VERSION 5.7 ;
BUSBITCHARS "[]" ;
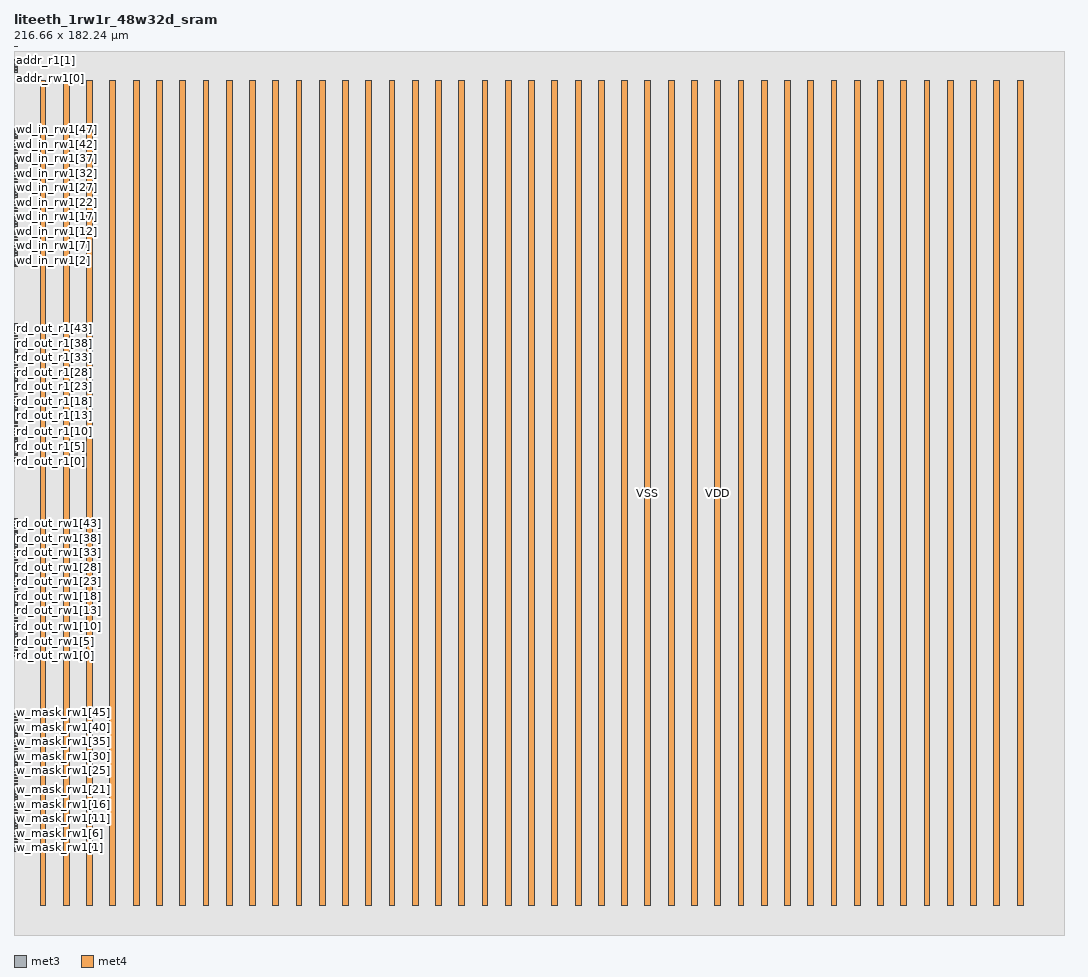
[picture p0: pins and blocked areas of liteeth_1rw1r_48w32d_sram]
MACRO liteeth_1rw1r_48w32d_sram
  FOREIGN liteeth_1rw1r_48w32d_sram 0 0 ;
  SYMMETRY X Y R90 ;
  SIZE 216.660 BY 182.240 ;
  CLASS BLOCK ;
  PIN w_mask_rw1[0]
    DIRECTION INPUT ;
    USE SIGNAL ;
    SHAPE ABUTMENT ;
    PORT
      LAYER met3 ;
      RECT 0.000 17.250 0.800 17.550 ;
    END
  END w_mask_rw1[0]
  PIN w_mask_rw1[1]
    DIRECTION INPUT ;
    USE SIGNAL ;
    SHAPE ABUTMENT ;
    PORT
      LAYER met3 ;
      RECT 0.000 17.850 0.800 18.150 ;
    END
  END w_mask_rw1[1]
  PIN w_mask_rw1[2]
    DIRECTION INPUT ;
    USE SIGNAL ;
    SHAPE ABUTMENT ;
    PORT
      LAYER met3 ;
      RECT 0.000 18.450 0.800 18.750 ;
    END
  END w_mask_rw1[2]
  PIN w_mask_rw1[3]
    DIRECTION INPUT ;
    USE SIGNAL ;
    SHAPE ABUTMENT ;
    PORT
      LAYER met3 ;
      RECT 0.000 19.050 0.800 19.350 ;
    END
  END w_mask_rw1[3]
  PIN w_mask_rw1[4]
    DIRECTION INPUT ;
    USE SIGNAL ;
    SHAPE ABUTMENT ;
    PORT
      LAYER met3 ;
      RECT 0.000 19.650 0.800 19.950 ;
    END
  END w_mask_rw1[4]
  PIN w_mask_rw1[5]
    DIRECTION INPUT ;
    USE SIGNAL ;
    SHAPE ABUTMENT ;
    PORT
      LAYER met3 ;
      RECT 0.000 20.250 0.800 20.550 ;
    END
  END w_mask_rw1[5]
  PIN w_mask_rw1[6]
    DIRECTION INPUT ;
    USE SIGNAL ;
    SHAPE ABUTMENT ;
    PORT
      LAYER met3 ;
      RECT 0.000 20.850 0.800 21.150 ;
    END
  END w_mask_rw1[6]
  PIN w_mask_rw1[7]
    DIRECTION INPUT ;
    USE SIGNAL ;
    SHAPE ABUTMENT ;
    PORT
      LAYER met3 ;
      RECT 0.000 21.450 0.800 21.750 ;
    END
  END w_mask_rw1[7]
  PIN w_mask_rw1[8]
    DIRECTION INPUT ;
    USE SIGNAL ;
    SHAPE ABUTMENT ;
    PORT
      LAYER met3 ;
      RECT 0.000 22.050 0.800 22.350 ;
    END
  END w_mask_rw1[8]
  PIN w_mask_rw1[9]
    DIRECTION INPUT ;
    USE SIGNAL ;
    SHAPE ABUTMENT ;
    PORT
      LAYER met3 ;
      RECT 0.000 22.650 0.800 22.950 ;
    END
  END w_mask_rw1[9]
  PIN w_mask_rw1[10]
    DIRECTION INPUT ;
    USE SIGNAL ;
    SHAPE ABUTMENT ;
    PORT
      LAYER met3 ;
      RECT 0.000 23.250 0.800 23.550 ;
    END
  END w_mask_rw1[10]
  PIN w_mask_rw1[11]
    DIRECTION INPUT ;
    USE SIGNAL ;
    SHAPE ABUTMENT ;
    PORT
      LAYER met3 ;
      RECT 0.000 23.850 0.800 24.150 ;
    END
  END w_mask_rw1[11]
  PIN w_mask_rw1[12]
    DIRECTION INPUT ;
    USE SIGNAL ;
    SHAPE ABUTMENT ;
    PORT
      LAYER met3 ;
      RECT 0.000 24.450 0.800 24.750 ;
    END
  END w_mask_rw1[12]
  PIN w_mask_rw1[13]
    DIRECTION INPUT ;
    USE SIGNAL ;
    SHAPE ABUTMENT ;
    PORT
      LAYER met3 ;
      RECT 0.000 25.050 0.800 25.350 ;
    END
  END w_mask_rw1[13]
  PIN w_mask_rw1[14]
    DIRECTION INPUT ;
    USE SIGNAL ;
    SHAPE ABUTMENT ;
    PORT
      LAYER met3 ;
      RECT 0.000 25.650 0.800 25.950 ;
    END
  END w_mask_rw1[14]
  PIN w_mask_rw1[15]
    DIRECTION INPUT ;
    USE SIGNAL ;
    SHAPE ABUTMENT ;
    PORT
      LAYER met3 ;
      RECT 0.000 26.250 0.800 26.550 ;
    END
  END w_mask_rw1[15]
  PIN w_mask_rw1[16]
    DIRECTION INPUT ;
    USE SIGNAL ;
    SHAPE ABUTMENT ;
    PORT
      LAYER met3 ;
      RECT 0.000 26.850 0.800 27.150 ;
    END
  END w_mask_rw1[16]
  PIN w_mask_rw1[17]
    DIRECTION INPUT ;
    USE SIGNAL ;
    SHAPE ABUTMENT ;
    PORT
      LAYER met3 ;
      RECT 0.000 27.450 0.800 27.750 ;
    END
  END w_mask_rw1[17]
  PIN w_mask_rw1[18]
    DIRECTION INPUT ;
    USE SIGNAL ;
    SHAPE ABUTMENT ;
    PORT
      LAYER met3 ;
      RECT 0.000 28.050 0.800 28.350 ;
    END
  END w_mask_rw1[18]
  PIN w_mask_rw1[19]
    DIRECTION INPUT ;
    USE SIGNAL ;
    SHAPE ABUTMENT ;
    PORT
      LAYER met3 ;
      RECT 0.000 28.650 0.800 28.950 ;
    END
  END w_mask_rw1[19]
  PIN w_mask_rw1[20]
    DIRECTION INPUT ;
    USE SIGNAL ;
    SHAPE ABUTMENT ;
    PORT
      LAYER met3 ;
      RECT 0.000 29.250 0.800 29.550 ;
    END
  END w_mask_rw1[20]
  PIN w_mask_rw1[21]
    DIRECTION INPUT ;
    USE SIGNAL ;
    SHAPE ABUTMENT ;
    PORT
      LAYER met3 ;
      RECT 0.000 29.850 0.800 30.150 ;
    END
  END w_mask_rw1[21]
  PIN w_mask_rw1[22]
    DIRECTION INPUT ;
    USE SIGNAL ;
    SHAPE ABUTMENT ;
    PORT
      LAYER met3 ;
      RECT 0.000 30.450 0.800 30.750 ;
    END
  END w_mask_rw1[22]
  PIN w_mask_rw1[23]
    DIRECTION INPUT ;
    USE SIGNAL ;
    SHAPE ABUTMENT ;
    PORT
      LAYER met3 ;
      RECT 0.000 31.050 0.800 31.350 ;
    END
  END w_mask_rw1[23]
  PIN w_mask_rw1[24]
    DIRECTION INPUT ;
    USE SIGNAL ;
    SHAPE ABUTMENT ;
    PORT
      LAYER met3 ;
      RECT 0.000 31.650 0.800 31.950 ;
    END
  END w_mask_rw1[24]
  PIN w_mask_rw1[25]
    DIRECTION INPUT ;
    USE SIGNAL ;
    SHAPE ABUTMENT ;
    PORT
      LAYER met3 ;
      RECT 0.000 32.250 0.800 32.550 ;
    END
  END w_mask_rw1[25]
  PIN w_mask_rw1[26]
    DIRECTION INPUT ;
    USE SIGNAL ;
    SHAPE ABUTMENT ;
    PORT
      LAYER met3 ;
      RECT 0.000 32.850 0.800 33.150 ;
    END
  END w_mask_rw1[26]
  PIN w_mask_rw1[27]
    DIRECTION INPUT ;
    USE SIGNAL ;
    SHAPE ABUTMENT ;
    PORT
      LAYER met3 ;
      RECT 0.000 33.450 0.800 33.750 ;
    END
  END w_mask_rw1[27]
  PIN w_mask_rw1[28]
    DIRECTION INPUT ;
    USE SIGNAL ;
    SHAPE ABUTMENT ;
    PORT
      LAYER met3 ;
      RECT 0.000 34.050 0.800 34.350 ;
    END
  END w_mask_rw1[28]
  PIN w_mask_rw1[29]
    DIRECTION INPUT ;
    USE SIGNAL ;
    SHAPE ABUTMENT ;
    PORT
      LAYER met3 ;
      RECT 0.000 34.650 0.800 34.950 ;
    END
  END w_mask_rw1[29]
  PIN w_mask_rw1[30]
    DIRECTION INPUT ;
    USE SIGNAL ;
    SHAPE ABUTMENT ;
    PORT
      LAYER met3 ;
      RECT 0.000 35.250 0.800 35.550 ;
    END
  END w_mask_rw1[30]
  PIN w_mask_rw1[31]
    DIRECTION INPUT ;
    USE SIGNAL ;
    SHAPE ABUTMENT ;
    PORT
      LAYER met3 ;
      RECT 0.000 35.850 0.800 36.150 ;
    END
  END w_mask_rw1[31]
  PIN w_mask_rw1[32]
    DIRECTION INPUT ;
    USE SIGNAL ;
    SHAPE ABUTMENT ;
    PORT
      LAYER met3 ;
      RECT 0.000 36.450 0.800 36.750 ;
    END
  END w_mask_rw1[32]
  PIN w_mask_rw1[33]
    DIRECTION INPUT ;
    USE SIGNAL ;
    SHAPE ABUTMENT ;
    PORT
      LAYER met3 ;
      RECT 0.000 37.050 0.800 37.350 ;
    END
  END w_mask_rw1[33]
  PIN w_mask_rw1[34]
    DIRECTION INPUT ;
    USE SIGNAL ;
    SHAPE ABUTMENT ;
    PORT
      LAYER met3 ;
      RECT 0.000 37.650 0.800 37.950 ;
    END
  END w_mask_rw1[34]
  PIN w_mask_rw1[35]
    DIRECTION INPUT ;
    USE SIGNAL ;
    SHAPE ABUTMENT ;
    PORT
      LAYER met3 ;
      RECT 0.000 38.250 0.800 38.550 ;
    END
  END w_mask_rw1[35]
  PIN w_mask_rw1[36]
    DIRECTION INPUT ;
    USE SIGNAL ;
    SHAPE ABUTMENT ;
    PORT
      LAYER met3 ;
      RECT 0.000 38.850 0.800 39.150 ;
    END
  END w_mask_rw1[36]
  PIN w_mask_rw1[37]
    DIRECTION INPUT ;
    USE SIGNAL ;
    SHAPE ABUTMENT ;
    PORT
      LAYER met3 ;
      RECT 0.000 39.450 0.800 39.750 ;
    END
  END w_mask_rw1[37]
  PIN w_mask_rw1[38]
    DIRECTION INPUT ;
    USE SIGNAL ;
    SHAPE ABUTMENT ;
    PORT
      LAYER met3 ;
      RECT 0.000 40.050 0.800 40.350 ;
    END
  END w_mask_rw1[38]
  PIN w_mask_rw1[39]
    DIRECTION INPUT ;
    USE SIGNAL ;
    SHAPE ABUTMENT ;
    PORT
      LAYER met3 ;
      RECT 0.000 40.650 0.800 40.950 ;
    END
  END w_mask_rw1[39]
  PIN w_mask_rw1[40]
    DIRECTION INPUT ;
    USE SIGNAL ;
    SHAPE ABUTMENT ;
    PORT
      LAYER met3 ;
      RECT 0.000 41.250 0.800 41.550 ;
    END
  END w_mask_rw1[40]
  PIN w_mask_rw1[41]
    DIRECTION INPUT ;
    USE SIGNAL ;
    SHAPE ABUTMENT ;
    PORT
      LAYER met3 ;
      RECT 0.000 41.850 0.800 42.150 ;
    END
  END w_mask_rw1[41]
  PIN w_mask_rw1[42]
    DIRECTION INPUT ;
    USE SIGNAL ;
    SHAPE ABUTMENT ;
    PORT
      LAYER met3 ;
      RECT 0.000 42.450 0.800 42.750 ;
    END
  END w_mask_rw1[42]
  PIN w_mask_rw1[43]
    DIRECTION INPUT ;
    USE SIGNAL ;
    SHAPE ABUTMENT ;
    PORT
      LAYER met3 ;
      RECT 0.000 43.050 0.800 43.350 ;
    END
  END w_mask_rw1[43]
  PIN w_mask_rw1[44]
    DIRECTION INPUT ;
    USE SIGNAL ;
    SHAPE ABUTMENT ;
    PORT
      LAYER met3 ;
      RECT 0.000 43.650 0.800 43.950 ;
    END
  END w_mask_rw1[44]
  PIN w_mask_rw1[45]
    DIRECTION INPUT ;
    USE SIGNAL ;
    SHAPE ABUTMENT ;
    PORT
      LAYER met3 ;
      RECT 0.000 44.250 0.800 44.550 ;
    END
  END w_mask_rw1[45]
  PIN w_mask_rw1[46]
    DIRECTION INPUT ;
    USE SIGNAL ;
    SHAPE ABUTMENT ;
    PORT
      LAYER met3 ;
      RECT 0.000 44.850 0.800 45.150 ;
    END
  END w_mask_rw1[46]
  PIN w_mask_rw1[47]
    DIRECTION INPUT ;
    USE SIGNAL ;
    SHAPE ABUTMENT ;
    PORT
      LAYER met3 ;
      RECT 0.000 45.450 0.800 45.750 ;
    END
  END w_mask_rw1[47]
  PIN rd_out_rw1[0]
    DIRECTION OUTPUT ;
    USE SIGNAL ;
    SHAPE ABUTMENT ;
    PORT
      LAYER met3 ;
      RECT 0.000 57.450 0.800 57.750 ;
    END
  END rd_out_rw1[0]
  PIN rd_out_rw1[1]
    DIRECTION OUTPUT ;
    USE SIGNAL ;
    SHAPE ABUTMENT ;
    PORT
      LAYER met3 ;
      RECT 0.000 58.050 0.800 58.350 ;
    END
  END rd_out_rw1[1]
  PIN rd_out_rw1[2]
    DIRECTION OUTPUT ;
    USE SIGNAL ;
    SHAPE ABUTMENT ;
    PORT
      LAYER met3 ;
      RECT 0.000 58.650 0.800 58.950 ;
    END
  END rd_out_rw1[2]
  PIN rd_out_rw1[3]
    DIRECTION OUTPUT ;
    USE SIGNAL ;
    SHAPE ABUTMENT ;
    PORT
      LAYER met3 ;
      RECT 0.000 59.250 0.800 59.550 ;
    END
  END rd_out_rw1[3]
  PIN rd_out_rw1[4]
    DIRECTION OUTPUT ;
    USE SIGNAL ;
    SHAPE ABUTMENT ;
    PORT
      LAYER met3 ;
      RECT 0.000 59.850 0.800 60.150 ;
    END
  END rd_out_rw1[4]
  PIN rd_out_rw1[5]
    DIRECTION OUTPUT ;
    USE SIGNAL ;
    SHAPE ABUTMENT ;
    PORT
      LAYER met3 ;
      RECT 0.000 60.450 0.800 60.750 ;
    END
  END rd_out_rw1[5]
  PIN rd_out_rw1[6]
    DIRECTION OUTPUT ;
    USE SIGNAL ;
    SHAPE ABUTMENT ;
    PORT
      LAYER met3 ;
      RECT 0.000 61.050 0.800 61.350 ;
    END
  END rd_out_rw1[6]
  PIN rd_out_rw1[7]
    DIRECTION OUTPUT ;
    USE SIGNAL ;
    SHAPE ABUTMENT ;
    PORT
      LAYER met3 ;
      RECT 0.000 61.650 0.800 61.950 ;
    END
  END rd_out_rw1[7]
  PIN rd_out_rw1[8]
    DIRECTION OUTPUT ;
    USE SIGNAL ;
    SHAPE ABUTMENT ;
    PORT
      LAYER met3 ;
      RECT 0.000 62.250 0.800 62.550 ;
    END
  END rd_out_rw1[8]
  PIN rd_out_rw1[9]
    DIRECTION OUTPUT ;
    USE SIGNAL ;
    SHAPE ABUTMENT ;
    PORT
      LAYER met3 ;
      RECT 0.000 62.850 0.800 63.150 ;
    END
  END rd_out_rw1[9]
  PIN rd_out_rw1[10]
    DIRECTION OUTPUT ;
    USE SIGNAL ;
    SHAPE ABUTMENT ;
    PORT
      LAYER met3 ;
      RECT 0.000 63.450 0.800 63.750 ;
    END
  END rd_out_rw1[10]
  PIN rd_out_rw1[11]
    DIRECTION OUTPUT ;
    USE SIGNAL ;
    SHAPE ABUTMENT ;
    PORT
      LAYER met3 ;
      RECT 0.000 64.050 0.800 64.350 ;
    END
  END rd_out_rw1[11]
  PIN rd_out_rw1[12]
    DIRECTION OUTPUT ;
    USE SIGNAL ;
    SHAPE ABUTMENT ;
    PORT
      LAYER met3 ;
      RECT 0.000 64.650 0.800 64.950 ;
    END
  END rd_out_rw1[12]
  PIN rd_out_rw1[13]
    DIRECTION OUTPUT ;
    USE SIGNAL ;
    SHAPE ABUTMENT ;
    PORT
      LAYER met3 ;
      RECT 0.000 65.250 0.800 65.550 ;
    END
  END rd_out_rw1[13]
  PIN rd_out_rw1[14]
    DIRECTION OUTPUT ;
    USE SIGNAL ;
    SHAPE ABUTMENT ;
    PORT
      LAYER met3 ;
      RECT 0.000 65.850 0.800 66.150 ;
    END
  END rd_out_rw1[14]
  PIN rd_out_rw1[15]
    DIRECTION OUTPUT ;
    USE SIGNAL ;
    SHAPE ABUTMENT ;
    PORT
      LAYER met3 ;
      RECT 0.000 66.450 0.800 66.750 ;
    END
  END rd_out_rw1[15]
  PIN rd_out_rw1[16]
    DIRECTION OUTPUT ;
    USE SIGNAL ;
    SHAPE ABUTMENT ;
    PORT
      LAYER met3 ;
      RECT 0.000 67.050 0.800 67.350 ;
    END
  END rd_out_rw1[16]
  PIN rd_out_rw1[17]
    DIRECTION OUTPUT ;
    USE SIGNAL ;
    SHAPE ABUTMENT ;
    PORT
      LAYER met3 ;
      RECT 0.000 67.650 0.800 67.950 ;
    END
  END rd_out_rw1[17]
  PIN rd_out_rw1[18]
    DIRECTION OUTPUT ;
    USE SIGNAL ;
    SHAPE ABUTMENT ;
    PORT
      LAYER met3 ;
      RECT 0.000 68.250 0.800 68.550 ;
    END
  END rd_out_rw1[18]
  PIN rd_out_rw1[19]
    DIRECTION OUTPUT ;
    USE SIGNAL ;
    SHAPE ABUTMENT ;
    PORT
      LAYER met3 ;
      RECT 0.000 68.850 0.800 69.150 ;
    END
  END rd_out_rw1[19]
  PIN rd_out_rw1[20]
    DIRECTION OUTPUT ;
    USE SIGNAL ;
    SHAPE ABUTMENT ;
    PORT
      LAYER met3 ;
      RECT 0.000 69.450 0.800 69.750 ;
    END
  END rd_out_rw1[20]
  PIN rd_out_rw1[21]
    DIRECTION OUTPUT ;
    USE SIGNAL ;
    SHAPE ABUTMENT ;
    PORT
      LAYER met3 ;
      RECT 0.000 70.050 0.800 70.350 ;
    END
  END rd_out_rw1[21]
  PIN rd_out_rw1[22]
    DIRECTION OUTPUT ;
    USE SIGNAL ;
    SHAPE ABUTMENT ;
    PORT
      LAYER met3 ;
      RECT 0.000 70.650 0.800 70.950 ;
    END
  END rd_out_rw1[22]
  PIN rd_out_rw1[23]
    DIRECTION OUTPUT ;
    USE SIGNAL ;
    SHAPE ABUTMENT ;
    PORT
      LAYER met3 ;
      RECT 0.000 71.250 0.800 71.550 ;
    END
  END rd_out_rw1[23]
  PIN rd_out_rw1[24]
    DIRECTION OUTPUT ;
    USE SIGNAL ;
    SHAPE ABUTMENT ;
    PORT
      LAYER met3 ;
      RECT 0.000 71.850 0.800 72.150 ;
    END
  END rd_out_rw1[24]
  PIN rd_out_rw1[25]
    DIRECTION OUTPUT ;
    USE SIGNAL ;
    SHAPE ABUTMENT ;
    PORT
      LAYER met3 ;
      RECT 0.000 72.450 0.800 72.750 ;
    END
  END rd_out_rw1[25]
  PIN rd_out_rw1[26]
    DIRECTION OUTPUT ;
    USE SIGNAL ;
    SHAPE ABUTMENT ;
    PORT
      LAYER met3 ;
      RECT 0.000 73.050 0.800 73.350 ;
    END
  END rd_out_rw1[26]
  PIN rd_out_rw1[27]
    DIRECTION OUTPUT ;
    USE SIGNAL ;
    SHAPE ABUTMENT ;
    PORT
      LAYER met3 ;
      RECT 0.000 73.650 0.800 73.950 ;
    END
  END rd_out_rw1[27]
  PIN rd_out_rw1[28]
    DIRECTION OUTPUT ;
    USE SIGNAL ;
    SHAPE ABUTMENT ;
    PORT
      LAYER met3 ;
      RECT 0.000 74.250 0.800 74.550 ;
    END
  END rd_out_rw1[28]
  PIN rd_out_rw1[29]
    DIRECTION OUTPUT ;
    USE SIGNAL ;
    SHAPE ABUTMENT ;
    PORT
      LAYER met3 ;
      RECT 0.000 74.850 0.800 75.150 ;
    END
  END rd_out_rw1[29]
  PIN rd_out_rw1[30]
    DIRECTION OUTPUT ;
    USE SIGNAL ;
    SHAPE ABUTMENT ;
    PORT
      LAYER met3 ;
      RECT 0.000 75.450 0.800 75.750 ;
    END
  END rd_out_rw1[30]
  PIN rd_out_rw1[31]
    DIRECTION OUTPUT ;
    USE SIGNAL ;
    SHAPE ABUTMENT ;
    PORT
      LAYER met3 ;
      RECT 0.000 76.050 0.800 76.350 ;
    END
  END rd_out_rw1[31]
  PIN rd_out_rw1[32]
    DIRECTION OUTPUT ;
    USE SIGNAL ;
    SHAPE ABUTMENT ;
    PORT
      LAYER met3 ;
      RECT 0.000 76.650 0.800 76.950 ;
    END
  END rd_out_rw1[32]
  PIN rd_out_rw1[33]
    DIRECTION OUTPUT ;
    USE SIGNAL ;
    SHAPE ABUTMENT ;
    PORT
      LAYER met3 ;
      RECT 0.000 77.250 0.800 77.550 ;
    END
  END rd_out_rw1[33]
  PIN rd_out_rw1[34]
    DIRECTION OUTPUT ;
    USE SIGNAL ;
    SHAPE ABUTMENT ;
    PORT
      LAYER met3 ;
      RECT 0.000 77.850 0.800 78.150 ;
    END
  END rd_out_rw1[34]
  PIN rd_out_rw1[35]
    DIRECTION OUTPUT ;
    USE SIGNAL ;
    SHAPE ABUTMENT ;
    PORT
      LAYER met3 ;
      RECT 0.000 78.450 0.800 78.750 ;
    END
  END rd_out_rw1[35]
  PIN rd_out_rw1[36]
    DIRECTION OUTPUT ;
    USE SIGNAL ;
    SHAPE ABUTMENT ;
    PORT
      LAYER met3 ;
      RECT 0.000 79.050 0.800 79.350 ;
    END
  END rd_out_rw1[36]
  PIN rd_out_rw1[37]
    DIRECTION OUTPUT ;
    USE SIGNAL ;
    SHAPE ABUTMENT ;
    PORT
      LAYER met3 ;
      RECT 0.000 79.650 0.800 79.950 ;
    END
  END rd_out_rw1[37]
  PIN rd_out_rw1[38]
    DIRECTION OUTPUT ;
    USE SIGNAL ;
    SHAPE ABUTMENT ;
    PORT
      LAYER met3 ;
      RECT 0.000 80.250 0.800 80.550 ;
    END
  END rd_out_rw1[38]
  PIN rd_out_rw1[39]
    DIRECTION OUTPUT ;
    USE SIGNAL ;
    SHAPE ABUTMENT ;
    PORT
      LAYER met3 ;
      RECT 0.000 80.850 0.800 81.150 ;
    END
  END rd_out_rw1[39]
  PIN rd_out_rw1[40]
    DIRECTION OUTPUT ;
    USE SIGNAL ;
    SHAPE ABUTMENT ;
    PORT
      LAYER met3 ;
      RECT 0.000 81.450 0.800 81.750 ;
    END
  END rd_out_rw1[40]
  PIN rd_out_rw1[41]
    DIRECTION OUTPUT ;
    USE SIGNAL ;
    SHAPE ABUTMENT ;
    PORT
      LAYER met3 ;
      RECT 0.000 82.050 0.800 82.350 ;
    END
  END rd_out_rw1[41]
  PIN rd_out_rw1[42]
    DIRECTION OUTPUT ;
    USE SIGNAL ;
    SHAPE ABUTMENT ;
    PORT
      LAYER met3 ;
      RECT 0.000 82.650 0.800 82.950 ;
    END
  END rd_out_rw1[42]
  PIN rd_out_rw1[43]
    DIRECTION OUTPUT ;
    USE SIGNAL ;
    SHAPE ABUTMENT ;
    PORT
      LAYER met3 ;
      RECT 0.000 83.250 0.800 83.550 ;
    END
  END rd_out_rw1[43]
  PIN rd_out_rw1[44]
    DIRECTION OUTPUT ;
    USE SIGNAL ;
    SHAPE ABUTMENT ;
    PORT
      LAYER met3 ;
      RECT 0.000 83.850 0.800 84.150 ;
    END
  END rd_out_rw1[44]
  PIN rd_out_rw1[45]
    DIRECTION OUTPUT ;
    USE SIGNAL ;
    SHAPE ABUTMENT ;
    PORT
      LAYER met3 ;
      RECT 0.000 84.450 0.800 84.750 ;
    END
  END rd_out_rw1[45]
  PIN rd_out_rw1[46]
    DIRECTION OUTPUT ;
    USE SIGNAL ;
    SHAPE ABUTMENT ;
    PORT
      LAYER met3 ;
      RECT 0.000 85.050 0.800 85.350 ;
    END
  END rd_out_rw1[46]
  PIN rd_out_rw1[47]
    DIRECTION OUTPUT ;
    USE SIGNAL ;
    SHAPE ABUTMENT ;
    PORT
      LAYER met3 ;
      RECT 0.000 85.650 0.800 85.950 ;
    END
  END rd_out_rw1[47]
  PIN rd_out_r1[0]
    DIRECTION OUTPUT ;
    USE SIGNAL ;
    SHAPE ABUTMENT ;
    PORT
      LAYER met3 ;
      RECT 0.000 97.650 0.800 97.950 ;
    END
  END rd_out_r1[0]
  PIN rd_out_r1[1]
    DIRECTION OUTPUT ;
    USE SIGNAL ;
    SHAPE ABUTMENT ;
    PORT
      LAYER met3 ;
      RECT 0.000 98.250 0.800 98.550 ;
    END
  END rd_out_r1[1]
  PIN rd_out_r1[2]
    DIRECTION OUTPUT ;
    USE SIGNAL ;
    SHAPE ABUTMENT ;
    PORT
      LAYER met3 ;
      RECT 0.000 98.850 0.800 99.150 ;
    END
  END rd_out_r1[2]
  PIN rd_out_r1[3]
    DIRECTION OUTPUT ;
    USE SIGNAL ;
    SHAPE ABUTMENT ;
    PORT
      LAYER met3 ;
      RECT 0.000 99.450 0.800 99.750 ;
    END
  END rd_out_r1[3]
  PIN rd_out_r1[4]
    DIRECTION OUTPUT ;
    USE SIGNAL ;
    SHAPE ABUTMENT ;
    PORT
      LAYER met3 ;
      RECT 0.000 100.050 0.800 100.350 ;
    END
  END rd_out_r1[4]
  PIN rd_out_r1[5]
    DIRECTION OUTPUT ;
    USE SIGNAL ;
    SHAPE ABUTMENT ;
    PORT
      LAYER met3 ;
      RECT 0.000 100.650 0.800 100.950 ;
    END
  END rd_out_r1[5]
  PIN rd_out_r1[6]
    DIRECTION OUTPUT ;
    USE SIGNAL ;
    SHAPE ABUTMENT ;
    PORT
      LAYER met3 ;
      RECT 0.000 101.250 0.800 101.550 ;
    END
  END rd_out_r1[6]
  PIN rd_out_r1[7]
    DIRECTION OUTPUT ;
    USE SIGNAL ;
    SHAPE ABUTMENT ;
    PORT
      LAYER met3 ;
      RECT 0.000 101.850 0.800 102.150 ;
    END
  END rd_out_r1[7]
  PIN rd_out_r1[8]
    DIRECTION OUTPUT ;
    USE SIGNAL ;
    SHAPE ABUTMENT ;
    PORT
      LAYER met3 ;
      RECT 0.000 102.450 0.800 102.750 ;
    END
  END rd_out_r1[8]
  PIN rd_out_r1[9]
    DIRECTION OUTPUT ;
    USE SIGNAL ;
    SHAPE ABUTMENT ;
    PORT
      LAYER met3 ;
      RECT 0.000 103.050 0.800 103.350 ;
    END
  END rd_out_r1[9]
  PIN rd_out_r1[10]
    DIRECTION OUTPUT ;
    USE SIGNAL ;
    SHAPE ABUTMENT ;
    PORT
      LAYER met3 ;
      RECT 0.000 103.650 0.800 103.950 ;
    END
  END rd_out_r1[10]
  PIN rd_out_r1[11]
    DIRECTION OUTPUT ;
    USE SIGNAL ;
    SHAPE ABUTMENT ;
    PORT
      LAYER met3 ;
      RECT 0.000 104.250 0.800 104.550 ;
    END
  END rd_out_r1[11]
  PIN rd_out_r1[12]
    DIRECTION OUTPUT ;
    USE SIGNAL ;
    SHAPE ABUTMENT ;
    PORT
      LAYER met3 ;
      RECT 0.000 104.850 0.800 105.150 ;
    END
  END rd_out_r1[12]
  PIN rd_out_r1[13]
    DIRECTION OUTPUT ;
    USE SIGNAL ;
    SHAPE ABUTMENT ;
    PORT
      LAYER met3 ;
      RECT 0.000 105.450 0.800 105.750 ;
    END
  END rd_out_r1[13]
  PIN rd_out_r1[14]
    DIRECTION OUTPUT ;
    USE SIGNAL ;
    SHAPE ABUTMENT ;
    PORT
      LAYER met3 ;
      RECT 0.000 106.050 0.800 106.350 ;
    END
  END rd_out_r1[14]
  PIN rd_out_r1[15]
    DIRECTION OUTPUT ;
    USE SIGNAL ;
    SHAPE ABUTMENT ;
    PORT
      LAYER met3 ;
      RECT 0.000 106.650 0.800 106.950 ;
    END
  END rd_out_r1[15]
  PIN rd_out_r1[16]
    DIRECTION OUTPUT ;
    USE SIGNAL ;
    SHAPE ABUTMENT ;
    PORT
      LAYER met3 ;
      RECT 0.000 107.250 0.800 107.550 ;
    END
  END rd_out_r1[16]
  PIN rd_out_r1[17]
    DIRECTION OUTPUT ;
    USE SIGNAL ;
    SHAPE ABUTMENT ;
    PORT
      LAYER met3 ;
      RECT 0.000 107.850 0.800 108.150 ;
    END
  END rd_out_r1[17]
  PIN rd_out_r1[18]
    DIRECTION OUTPUT ;
    USE SIGNAL ;
    SHAPE ABUTMENT ;
    PORT
      LAYER met3 ;
      RECT 0.000 108.450 0.800 108.750 ;
    END
  END rd_out_r1[18]
  PIN rd_out_r1[19]
    DIRECTION OUTPUT ;
    USE SIGNAL ;
    SHAPE ABUTMENT ;
    PORT
      LAYER met3 ;
      RECT 0.000 109.050 0.800 109.350 ;
    END
  END rd_out_r1[19]
  PIN rd_out_r1[20]
    DIRECTION OUTPUT ;
    USE SIGNAL ;
    SHAPE ABUTMENT ;
    PORT
      LAYER met3 ;
      RECT 0.000 109.650 0.800 109.950 ;
    END
  END rd_out_r1[20]
  PIN rd_out_r1[21]
    DIRECTION OUTPUT ;
    USE SIGNAL ;
    SHAPE ABUTMENT ;
    PORT
      LAYER met3 ;
      RECT 0.000 110.250 0.800 110.550 ;
    END
  END rd_out_r1[21]
  PIN rd_out_r1[22]
    DIRECTION OUTPUT ;
    USE SIGNAL ;
    SHAPE ABUTMENT ;
    PORT
      LAYER met3 ;
      RECT 0.000 110.850 0.800 111.150 ;
    END
  END rd_out_r1[22]
  PIN rd_out_r1[23]
    DIRECTION OUTPUT ;
    USE SIGNAL ;
    SHAPE ABUTMENT ;
    PORT
      LAYER met3 ;
      RECT 0.000 111.450 0.800 111.750 ;
    END
  END rd_out_r1[23]
  PIN rd_out_r1[24]
    DIRECTION OUTPUT ;
    USE SIGNAL ;
    SHAPE ABUTMENT ;
    PORT
      LAYER met3 ;
      RECT 0.000 112.050 0.800 112.350 ;
    END
  END rd_out_r1[24]
  PIN rd_out_r1[25]
    DIRECTION OUTPUT ;
    USE SIGNAL ;
    SHAPE ABUTMENT ;
    PORT
      LAYER met3 ;
      RECT 0.000 112.650 0.800 112.950 ;
    END
  END rd_out_r1[25]
  PIN rd_out_r1[26]
    DIRECTION OUTPUT ;
    USE SIGNAL ;
    SHAPE ABUTMENT ;
    PORT
      LAYER met3 ;
      RECT 0.000 113.250 0.800 113.550 ;
    END
  END rd_out_r1[26]
  PIN rd_out_r1[27]
    DIRECTION OUTPUT ;
    USE SIGNAL ;
    SHAPE ABUTMENT ;
    PORT
      LAYER met3 ;
      RECT 0.000 113.850 0.800 114.150 ;
    END
  END rd_out_r1[27]
  PIN rd_out_r1[28]
    DIRECTION OUTPUT ;
    USE SIGNAL ;
    SHAPE ABUTMENT ;
    PORT
      LAYER met3 ;
      RECT 0.000 114.450 0.800 114.750 ;
    END
  END rd_out_r1[28]
  PIN rd_out_r1[29]
    DIRECTION OUTPUT ;
    USE SIGNAL ;
    SHAPE ABUTMENT ;
    PORT
      LAYER met3 ;
      RECT 0.000 115.050 0.800 115.350 ;
    END
  END rd_out_r1[29]
  PIN rd_out_r1[30]
    DIRECTION OUTPUT ;
    USE SIGNAL ;
    SHAPE ABUTMENT ;
    PORT
      LAYER met3 ;
      RECT 0.000 115.650 0.800 115.950 ;
    END
  END rd_out_r1[30]
  PIN rd_out_r1[31]
    DIRECTION OUTPUT ;
    USE SIGNAL ;
    SHAPE ABUTMENT ;
    PORT
      LAYER met3 ;
      RECT 0.000 116.250 0.800 116.550 ;
    END
  END rd_out_r1[31]
  PIN rd_out_r1[32]
    DIRECTION OUTPUT ;
    USE SIGNAL ;
    SHAPE ABUTMENT ;
    PORT
      LAYER met3 ;
      RECT 0.000 116.850 0.800 117.150 ;
    END
  END rd_out_r1[32]
  PIN rd_out_r1[33]
    DIRECTION OUTPUT ;
    USE SIGNAL ;
    SHAPE ABUTMENT ;
    PORT
      LAYER met3 ;
      RECT 0.000 117.450 0.800 117.750 ;
    END
  END rd_out_r1[33]
  PIN rd_out_r1[34]
    DIRECTION OUTPUT ;
    USE SIGNAL ;
    SHAPE ABUTMENT ;
    PORT
      LAYER met3 ;
      RECT 0.000 118.050 0.800 118.350 ;
    END
  END rd_out_r1[34]
  PIN rd_out_r1[35]
    DIRECTION OUTPUT ;
    USE SIGNAL ;
    SHAPE ABUTMENT ;
    PORT
      LAYER met3 ;
      RECT 0.000 118.650 0.800 118.950 ;
    END
  END rd_out_r1[35]
  PIN rd_out_r1[36]
    DIRECTION OUTPUT ;
    USE SIGNAL ;
    SHAPE ABUTMENT ;
    PORT
      LAYER met3 ;
      RECT 0.000 119.250 0.800 119.550 ;
    END
  END rd_out_r1[36]
  PIN rd_out_r1[37]
    DIRECTION OUTPUT ;
    USE SIGNAL ;
    SHAPE ABUTMENT ;
    PORT
      LAYER met3 ;
      RECT 0.000 119.850 0.800 120.150 ;
    END
  END rd_out_r1[37]
  PIN rd_out_r1[38]
    DIRECTION OUTPUT ;
    USE SIGNAL ;
    SHAPE ABUTMENT ;
    PORT
      LAYER met3 ;
      RECT 0.000 120.450 0.800 120.750 ;
    END
  END rd_out_r1[38]
  PIN rd_out_r1[39]
    DIRECTION OUTPUT ;
    USE SIGNAL ;
    SHAPE ABUTMENT ;
    PORT
      LAYER met3 ;
      RECT 0.000 121.050 0.800 121.350 ;
    END
  END rd_out_r1[39]
  PIN rd_out_r1[40]
    DIRECTION OUTPUT ;
    USE SIGNAL ;
    SHAPE ABUTMENT ;
    PORT
      LAYER met3 ;
      RECT 0.000 121.650 0.800 121.950 ;
    END
  END rd_out_r1[40]
  PIN rd_out_r1[41]
    DIRECTION OUTPUT ;
    USE SIGNAL ;
    SHAPE ABUTMENT ;
    PORT
      LAYER met3 ;
      RECT 0.000 122.250 0.800 122.550 ;
    END
  END rd_out_r1[41]
  PIN rd_out_r1[42]
    DIRECTION OUTPUT ;
    USE SIGNAL ;
    SHAPE ABUTMENT ;
    PORT
      LAYER met3 ;
      RECT 0.000 122.850 0.800 123.150 ;
    END
  END rd_out_r1[42]
  PIN rd_out_r1[43]
    DIRECTION OUTPUT ;
    USE SIGNAL ;
    SHAPE ABUTMENT ;
    PORT
      LAYER met3 ;
      RECT 0.000 123.450 0.800 123.750 ;
    END
  END rd_out_r1[43]
  PIN rd_out_r1[44]
    DIRECTION OUTPUT ;
    USE SIGNAL ;
    SHAPE ABUTMENT ;
    PORT
      LAYER met3 ;
      RECT 0.000 124.050 0.800 124.350 ;
    END
  END rd_out_r1[44]
  PIN rd_out_r1[45]
    DIRECTION OUTPUT ;
    USE SIGNAL ;
    SHAPE ABUTMENT ;
    PORT
      LAYER met3 ;
      RECT 0.000 124.650 0.800 124.950 ;
    END
  END rd_out_r1[45]
  PIN rd_out_r1[46]
    DIRECTION OUTPUT ;
    USE SIGNAL ;
    SHAPE ABUTMENT ;
    PORT
      LAYER met3 ;
      RECT 0.000 125.250 0.800 125.550 ;
    END
  END rd_out_r1[46]
  PIN rd_out_r1[47]
    DIRECTION OUTPUT ;
    USE SIGNAL ;
    SHAPE ABUTMENT ;
    PORT
      LAYER met3 ;
      RECT 0.000 125.850 0.800 126.150 ;
    END
  END rd_out_r1[47]
  PIN wd_in_rw1[0]
    DIRECTION INPUT ;
    USE SIGNAL ;
    SHAPE ABUTMENT ;
    PORT
      LAYER met3 ;
      RECT 0.000 137.850 0.800 138.150 ;
    END
  END wd_in_rw1[0]
  PIN wd_in_rw1[1]
    DIRECTION INPUT ;
    USE SIGNAL ;
    SHAPE ABUTMENT ;
    PORT
      LAYER met3 ;
      RECT 0.000 138.450 0.800 138.750 ;
    END
  END wd_in_rw1[1]
  PIN wd_in_rw1[2]
    DIRECTION INPUT ;
    USE SIGNAL ;
    SHAPE ABUTMENT ;
    PORT
      LAYER met3 ;
      RECT 0.000 139.050 0.800 139.350 ;
    END
  END wd_in_rw1[2]
  PIN wd_in_rw1[3]
    DIRECTION INPUT ;
    USE SIGNAL ;
    SHAPE ABUTMENT ;
    PORT
      LAYER met3 ;
      RECT 0.000 139.650 0.800 139.950 ;
    END
  END wd_in_rw1[3]
  PIN wd_in_rw1[4]
    DIRECTION INPUT ;
    USE SIGNAL ;
    SHAPE ABUTMENT ;
    PORT
      LAYER met3 ;
      RECT 0.000 140.250 0.800 140.550 ;
    END
  END wd_in_rw1[4]
  PIN wd_in_rw1[5]
    DIRECTION INPUT ;
    USE SIGNAL ;
    SHAPE ABUTMENT ;
    PORT
      LAYER met3 ;
      RECT 0.000 140.850 0.800 141.150 ;
    END
  END wd_in_rw1[5]
  PIN wd_in_rw1[6]
    DIRECTION INPUT ;
    USE SIGNAL ;
    SHAPE ABUTMENT ;
    PORT
      LAYER met3 ;
      RECT 0.000 141.450 0.800 141.750 ;
    END
  END wd_in_rw1[6]
  PIN wd_in_rw1[7]
    DIRECTION INPUT ;
    USE SIGNAL ;
    SHAPE ABUTMENT ;
    PORT
      LAYER met3 ;
      RECT 0.000 142.050 0.800 142.350 ;
    END
  END wd_in_rw1[7]
  PIN wd_in_rw1[8]
    DIRECTION INPUT ;
    USE SIGNAL ;
    SHAPE ABUTMENT ;
    PORT
      LAYER met3 ;
      RECT 0.000 142.650 0.800 142.950 ;
    END
  END wd_in_rw1[8]
  PIN wd_in_rw1[9]
    DIRECTION INPUT ;
    USE SIGNAL ;
    SHAPE ABUTMENT ;
    PORT
      LAYER met3 ;
      RECT 0.000 143.250 0.800 143.550 ;
    END
  END wd_in_rw1[9]
  PIN wd_in_rw1[10]
    DIRECTION INPUT ;
    USE SIGNAL ;
    SHAPE ABUTMENT ;
    PORT
      LAYER met3 ;
      RECT 0.000 143.850 0.800 144.150 ;
    END
  END wd_in_rw1[10]
  PIN wd_in_rw1[11]
    DIRECTION INPUT ;
    USE SIGNAL ;
    SHAPE ABUTMENT ;
    PORT
      LAYER met3 ;
      RECT 0.000 144.450 0.800 144.750 ;
    END
  END wd_in_rw1[11]
  PIN wd_in_rw1[12]
    DIRECTION INPUT ;
    USE SIGNAL ;
    SHAPE ABUTMENT ;
    PORT
      LAYER met3 ;
      RECT 0.000 145.050 0.800 145.350 ;
    END
  END wd_in_rw1[12]
  PIN wd_in_rw1[13]
    DIRECTION INPUT ;
    USE SIGNAL ;
    SHAPE ABUTMENT ;
    PORT
      LAYER met3 ;
      RECT 0.000 145.650 0.800 145.950 ;
    END
  END wd_in_rw1[13]
  PIN wd_in_rw1[14]
    DIRECTION INPUT ;
    USE SIGNAL ;
    SHAPE ABUTMENT ;
    PORT
      LAYER met3 ;
      RECT 0.000 146.250 0.800 146.550 ;
    END
  END wd_in_rw1[14]
  PIN wd_in_rw1[15]
    DIRECTION INPUT ;
    USE SIGNAL ;
    SHAPE ABUTMENT ;
    PORT
      LAYER met3 ;
      RECT 0.000 146.850 0.800 147.150 ;
    END
  END wd_in_rw1[15]
  PIN wd_in_rw1[16]
    DIRECTION INPUT ;
    USE SIGNAL ;
    SHAPE ABUTMENT ;
    PORT
      LAYER met3 ;
      RECT 0.000 147.450 0.800 147.750 ;
    END
  END wd_in_rw1[16]
  PIN wd_in_rw1[17]
    DIRECTION INPUT ;
    USE SIGNAL ;
    SHAPE ABUTMENT ;
    PORT
      LAYER met3 ;
      RECT 0.000 148.050 0.800 148.350 ;
    END
  END wd_in_rw1[17]
  PIN wd_in_rw1[18]
    DIRECTION INPUT ;
    USE SIGNAL ;
    SHAPE ABUTMENT ;
    PORT
      LAYER met3 ;
      RECT 0.000 148.650 0.800 148.950 ;
    END
  END wd_in_rw1[18]
  PIN wd_in_rw1[19]
    DIRECTION INPUT ;
    USE SIGNAL ;
    SHAPE ABUTMENT ;
    PORT
      LAYER met3 ;
      RECT 0.000 149.250 0.800 149.550 ;
    END
  END wd_in_rw1[19]
  PIN wd_in_rw1[20]
    DIRECTION INPUT ;
    USE SIGNAL ;
    SHAPE ABUTMENT ;
    PORT
      LAYER met3 ;
      RECT 0.000 149.850 0.800 150.150 ;
    END
  END wd_in_rw1[20]
  PIN wd_in_rw1[21]
    DIRECTION INPUT ;
    USE SIGNAL ;
    SHAPE ABUTMENT ;
    PORT
      LAYER met3 ;
      RECT 0.000 150.450 0.800 150.750 ;
    END
  END wd_in_rw1[21]
  PIN wd_in_rw1[22]
    DIRECTION INPUT ;
    USE SIGNAL ;
    SHAPE ABUTMENT ;
    PORT
      LAYER met3 ;
      RECT 0.000 151.050 0.800 151.350 ;
    END
  END wd_in_rw1[22]
  PIN wd_in_rw1[23]
    DIRECTION INPUT ;
    USE SIGNAL ;
    SHAPE ABUTMENT ;
    PORT
      LAYER met3 ;
      RECT 0.000 151.650 0.800 151.950 ;
    END
  END wd_in_rw1[23]
  PIN wd_in_rw1[24]
    DIRECTION INPUT ;
    USE SIGNAL ;
    SHAPE ABUTMENT ;
    PORT
      LAYER met3 ;
      RECT 0.000 152.250 0.800 152.550 ;
    END
  END wd_in_rw1[24]
  PIN wd_in_rw1[25]
    DIRECTION INPUT ;
    USE SIGNAL ;
    SHAPE ABUTMENT ;
    PORT
      LAYER met3 ;
      RECT 0.000 152.850 0.800 153.150 ;
    END
  END wd_in_rw1[25]
  PIN wd_in_rw1[26]
    DIRECTION INPUT ;
    USE SIGNAL ;
    SHAPE ABUTMENT ;
    PORT
      LAYER met3 ;
      RECT 0.000 153.450 0.800 153.750 ;
    END
  END wd_in_rw1[26]
  PIN wd_in_rw1[27]
    DIRECTION INPUT ;
    USE SIGNAL ;
    SHAPE ABUTMENT ;
    PORT
      LAYER met3 ;
      RECT 0.000 154.050 0.800 154.350 ;
    END
  END wd_in_rw1[27]
  PIN wd_in_rw1[28]
    DIRECTION INPUT ;
    USE SIGNAL ;
    SHAPE ABUTMENT ;
    PORT
      LAYER met3 ;
      RECT 0.000 154.650 0.800 154.950 ;
    END
  END wd_in_rw1[28]
  PIN wd_in_rw1[29]
    DIRECTION INPUT ;
    USE SIGNAL ;
    SHAPE ABUTMENT ;
    PORT
      LAYER met3 ;
      RECT 0.000 155.250 0.800 155.550 ;
    END
  END wd_in_rw1[29]
  PIN wd_in_rw1[30]
    DIRECTION INPUT ;
    USE SIGNAL ;
    SHAPE ABUTMENT ;
    PORT
      LAYER met3 ;
      RECT 0.000 155.850 0.800 156.150 ;
    END
  END wd_in_rw1[30]
  PIN wd_in_rw1[31]
    DIRECTION INPUT ;
    USE SIGNAL ;
    SHAPE ABUTMENT ;
    PORT
      LAYER met3 ;
      RECT 0.000 156.450 0.800 156.750 ;
    END
  END wd_in_rw1[31]
  PIN wd_in_rw1[32]
    DIRECTION INPUT ;
    USE SIGNAL ;
    SHAPE ABUTMENT ;
    PORT
      LAYER met3 ;
      RECT 0.000 157.050 0.800 157.350 ;
    END
  END wd_in_rw1[32]
  PIN wd_in_rw1[33]
    DIRECTION INPUT ;
    USE SIGNAL ;
    SHAPE ABUTMENT ;
    PORT
      LAYER met3 ;
      RECT 0.000 157.650 0.800 157.950 ;
    END
  END wd_in_rw1[33]
  PIN wd_in_rw1[34]
    DIRECTION INPUT ;
    USE SIGNAL ;
    SHAPE ABUTMENT ;
    PORT
      LAYER met3 ;
      RECT 0.000 158.250 0.800 158.550 ;
    END
  END wd_in_rw1[34]
  PIN wd_in_rw1[35]
    DIRECTION INPUT ;
    USE SIGNAL ;
    SHAPE ABUTMENT ;
    PORT
      LAYER met3 ;
      RECT 0.000 158.850 0.800 159.150 ;
    END
  END wd_in_rw1[35]
  PIN wd_in_rw1[36]
    DIRECTION INPUT ;
    USE SIGNAL ;
    SHAPE ABUTMENT ;
    PORT
      LAYER met3 ;
      RECT 0.000 159.450 0.800 159.750 ;
    END
  END wd_in_rw1[36]
  PIN wd_in_rw1[37]
    DIRECTION INPUT ;
    USE SIGNAL ;
    SHAPE ABUTMENT ;
    PORT
      LAYER met3 ;
      RECT 0.000 160.050 0.800 160.350 ;
    END
  END wd_in_rw1[37]
  PIN wd_in_rw1[38]
    DIRECTION INPUT ;
    USE SIGNAL ;
    SHAPE ABUTMENT ;
    PORT
      LAYER met3 ;
      RECT 0.000 160.650 0.800 160.950 ;
    END
  END wd_in_rw1[38]
  PIN wd_in_rw1[39]
    DIRECTION INPUT ;
    USE SIGNAL ;
    SHAPE ABUTMENT ;
    PORT
      LAYER met3 ;
      RECT 0.000 161.250 0.800 161.550 ;
    END
  END wd_in_rw1[39]
  PIN wd_in_rw1[40]
    DIRECTION INPUT ;
    USE SIGNAL ;
    SHAPE ABUTMENT ;
    PORT
      LAYER met3 ;
      RECT 0.000 161.850 0.800 162.150 ;
    END
  END wd_in_rw1[40]
  PIN wd_in_rw1[41]
    DIRECTION INPUT ;
    USE SIGNAL ;
    SHAPE ABUTMENT ;
    PORT
      LAYER met3 ;
      RECT 0.000 162.450 0.800 162.750 ;
    END
  END wd_in_rw1[41]
  PIN wd_in_rw1[42]
    DIRECTION INPUT ;
    USE SIGNAL ;
    SHAPE ABUTMENT ;
    PORT
      LAYER met3 ;
      RECT 0.000 163.050 0.800 163.350 ;
    END
  END wd_in_rw1[42]
  PIN wd_in_rw1[43]
    DIRECTION INPUT ;
    USE SIGNAL ;
    SHAPE ABUTMENT ;
    PORT
      LAYER met3 ;
      RECT 0.000 163.650 0.800 163.950 ;
    END
  END wd_in_rw1[43]
  PIN wd_in_rw1[44]
    DIRECTION INPUT ;
    USE SIGNAL ;
    SHAPE ABUTMENT ;
    PORT
      LAYER met3 ;
      RECT 0.000 164.250 0.800 164.550 ;
    END
  END wd_in_rw1[44]
  PIN wd_in_rw1[45]
    DIRECTION INPUT ;
    USE SIGNAL ;
    SHAPE ABUTMENT ;
    PORT
      LAYER met3 ;
      RECT 0.000 164.850 0.800 165.150 ;
    END
  END wd_in_rw1[45]
  PIN wd_in_rw1[46]
    DIRECTION INPUT ;
    USE SIGNAL ;
    SHAPE ABUTMENT ;
    PORT
      LAYER met3 ;
      RECT 0.000 165.450 0.800 165.750 ;
    END
  END wd_in_rw1[46]
  PIN wd_in_rw1[47]
    DIRECTION INPUT ;
    USE SIGNAL ;
    SHAPE ABUTMENT ;
    PORT
      LAYER met3 ;
      RECT 0.000 166.050 0.800 166.350 ;
    END
  END wd_in_rw1[47]
  PIN addr_rw1[0]
    DIRECTION INPUT ;
    USE SIGNAL ;
    SHAPE ABUTMENT ;
    PORT
      LAYER met3 ;
      RECT 0.000 178.050 0.800 178.350 ;
    END
  END addr_rw1[0]
  PIN addr_rw1[1]
    DIRECTION INPUT ;
    USE SIGNAL ;
    SHAPE ABUTMENT ;
    PORT
      LAYER met3 ;
      RECT 0.000 178.650 0.800 178.950 ;
    END
  END addr_rw1[1]
  PIN addr_rw1[2]
    DIRECTION INPUT ;
    USE SIGNAL ;
    SHAPE ABUTMENT ;
    PORT
      LAYER met3 ;
      RECT 0.000 179.250 0.800 179.550 ;
    END
  END addr_rw1[2]
  PIN addr_rw1[3]
    DIRECTION INPUT ;
    USE SIGNAL ;
    SHAPE ABUTMENT ;
    PORT
      LAYER met3 ;
      RECT 0.000 179.850 0.800 180.150 ;
    END
  END addr_rw1[3]
  PIN addr_rw1[4]
    DIRECTION INPUT ;
    USE SIGNAL ;
    SHAPE ABUTMENT ;
    PORT
      LAYER met3 ;
      RECT 0.000 180.450 0.800 180.750 ;
    END
  END addr_rw1[4]
  PIN addr_r1[0]
    DIRECTION INPUT ;
    USE SIGNAL ;
    SHAPE ABUTMENT ;
    PORT
      LAYER met3 ;
      RECT 0.000 192.450 0.800 192.750 ;
    END
  END addr_r1[0]
  PIN addr_r1[1]
    DIRECTION INPUT ;
    USE SIGNAL ;
    SHAPE ABUTMENT ;
    PORT
      LAYER met3 ;
      RECT 0.000 193.050 0.800 193.350 ;
    END
  END addr_r1[1]
  PIN addr_r1[2]
    DIRECTION INPUT ;
    USE SIGNAL ;
    SHAPE ABUTMENT ;
    PORT
      LAYER met3 ;
      RECT 0.000 193.650 0.800 193.950 ;
    END
  END addr_r1[2]
  PIN addr_r1[3]
    DIRECTION INPUT ;
    USE SIGNAL ;
    SHAPE ABUTMENT ;
    PORT
      LAYER met3 ;
      RECT 0.000 194.250 0.800 194.550 ;
    END
  END addr_r1[3]
  PIN addr_r1[4]
    DIRECTION INPUT ;
    USE SIGNAL ;
    SHAPE ABUTMENT ;
    PORT
      LAYER met3 ;
      RECT 0.000 194.850 0.800 195.150 ;
    END
  END addr_r1[4]
  PIN we_in_rw1
    DIRECTION INPUT ;
    USE SIGNAL ;
    SHAPE ABUTMENT ;
    PORT
      LAYER met3 ;
      RECT 0.000 206.850 0.800 207.150 ;
    END
  END we_in_rw1
  PIN ce_rw1
    DIRECTION INPUT ;
    USE SIGNAL ;
    SHAPE ABUTMENT ;
    PORT
      LAYER met3 ;
      RECT 0.000 230.250 0.800 230.550 ;
    END
  END ce_rw1
  PIN ce_r1
    DIRECTION INPUT ;
    USE SIGNAL ;
    SHAPE ABUTMENT ;
    PORT
      LAYER met3 ;
      RECT 0.000 253.650 0.800 253.950 ;
    END
  END ce_r1
  PIN clk0
    DIRECTION INPUT ;
    USE SIGNAL ;
    SHAPE ABUTMENT ;
    PORT
      LAYER met3 ;
      RECT 0.000 265.650 0.800 265.950 ;
    END
  END clk0
  PIN clk1
    DIRECTION INPUT ;
    USE SIGNAL ;
    SHAPE ABUTMENT ;
    PORT
      LAYER met3 ;
      RECT 0.000 266.250 0.800 266.550 ;
    END
  END clk1
  PIN VSS
    DIRECTION INOUT ;
    USE GROUND ;
    PORT
      LAYER met4 ;
      RECT 5.400 6.000 6.600 176.240 ;
      RECT 15.000 6.000 16.200 176.240 ;
      RECT 24.600 6.000 25.800 176.240 ;
      RECT 34.200 6.000 35.400 176.240 ;
      RECT 43.800 6.000 45.000 176.240 ;
      RECT 53.400 6.000 54.600 176.240 ;
      RECT 63.000 6.000 64.200 176.240 ;
      RECT 72.600 6.000 73.800 176.240 ;
      RECT 82.200 6.000 83.400 176.240 ;
      RECT 91.800 6.000 93.000 176.240 ;
      RECT 101.400 6.000 102.600 176.240 ;
      RECT 111.000 6.000 112.200 176.240 ;
      RECT 120.600 6.000 121.800 176.240 ;
      RECT 130.200 6.000 131.400 176.240 ;
      RECT 139.800 6.000 141.000 176.240 ;
      RECT 149.400 6.000 150.600 176.240 ;
      RECT 159.000 6.000 160.200 176.240 ;
      RECT 168.600 6.000 169.800 176.240 ;
      RECT 178.200 6.000 179.400 176.240 ;
      RECT 187.800 6.000 189.000 176.240 ;
      RECT 197.400 6.000 198.600 176.240 ;
      RECT 207.000 6.000 208.200 176.240 ;
    END
  END VSS
  PIN VDD
    DIRECTION INOUT ;
    USE POWER ;
    PORT
      LAYER met4 ;
      RECT 10.200 6.000 11.400 176.240 ;
      RECT 19.800 6.000 21.000 176.240 ;
      RECT 29.400 6.000 30.600 176.240 ;
      RECT 39.000 6.000 40.200 176.240 ;
      RECT 48.600 6.000 49.800 176.240 ;
      RECT 58.200 6.000 59.400 176.240 ;
      RECT 67.800 6.000 69.000 176.240 ;
      RECT 77.400 6.000 78.600 176.240 ;
      RECT 87.000 6.000 88.200 176.240 ;
      RECT 96.600 6.000 97.800 176.240 ;
      RECT 106.200 6.000 107.400 176.240 ;
      RECT 115.800 6.000 117.000 176.240 ;
      RECT 125.400 6.000 126.600 176.240 ;
      RECT 135.000 6.000 136.200 176.240 ;
      RECT 144.600 6.000 145.800 176.240 ;
      RECT 154.200 6.000 155.400 176.240 ;
      RECT 163.800 6.000 165.000 176.240 ;
      RECT 173.400 6.000 174.600 176.240 ;
      RECT 183.000 6.000 184.200 176.240 ;
      RECT 192.600 6.000 193.800 176.240 ;
      RECT 202.200 6.000 203.400 176.240 ;
    END
  END VDD
  OBS
    LAYER met1 ;
    RECT 0 0 216.660 182.240 ;
    LAYER met2 ;
    RECT 0 0 216.660 182.240 ;
    LAYER met3 ;
    RECT 0.800 0 216.660 182.240 ;
    RECT 0 0.000 0.800 5.850 ;
    RECT 0 6.150 0.800 6.450 ;
    RECT 0 6.750 0.800 7.050 ;
    RECT 0 7.350 0.800 7.650 ;
    RECT 0 7.950 0.800 8.250 ;
    RECT 0 8.550 0.800 8.850 ;
    RECT 0 9.150 0.800 9.450 ;
    RECT 0 9.750 0.800 10.050 ;
    RECT 0 10.350 0.800 10.650 ;
    RECT 0 10.950 0.800 11.250 ;
    RECT 0 11.550 0.800 11.850 ;
    RECT 0 12.150 0.800 12.450 ;
    RECT 0 12.750 0.800 13.050 ;
    RECT 0 13.350 0.800 13.650 ;
    RECT 0 13.950 0.800 14.250 ;
    RECT 0 14.550 0.800 14.850 ;
    RECT 0 15.150 0.800 15.450 ;
    RECT 0 15.750 0.800 16.050 ;
    RECT 0 16.350 0.800 16.650 ;
    RECT 0 16.950 0.800 17.250 ;
    RECT 0 17.550 0.800 17.850 ;
    RECT 0 18.150 0.800 18.450 ;
    RECT 0 18.750 0.800 19.050 ;
    RECT 0 19.350 0.800 19.650 ;
    RECT 0 19.950 0.800 20.250 ;
    RECT 0 20.550 0.800 20.850 ;
    RECT 0 21.150 0.800 21.450 ;
    RECT 0 21.750 0.800 22.050 ;
    RECT 0 22.350 0.800 22.650 ;
    RECT 0 22.950 0.800 23.250 ;
    RECT 0 23.550 0.800 23.850 ;
    RECT 0 24.150 0.800 24.450 ;
    RECT 0 24.750 0.800 25.050 ;
    RECT 0 25.350 0.800 25.650 ;
    RECT 0 25.950 0.800 26.250 ;
    RECT 0 26.550 0.800 26.850 ;
    RECT 0 27.150 0.800 27.450 ;
    RECT 0 27.750 0.800 28.050 ;
    RECT 0 28.350 0.800 28.650 ;
    RECT 0 28.950 0.800 29.250 ;
    RECT 0 29.550 0.800 29.850 ;
    RECT 0 30.150 0.800 30.450 ;
    RECT 0 30.750 0.800 31.050 ;
    RECT 0 31.350 0.800 31.650 ;
    RECT 0 31.950 0.800 32.250 ;
    RECT 0 32.550 0.800 32.850 ;
    RECT 0 33.150 0.800 33.450 ;
    RECT 0 33.750 0.800 34.050 ;
    RECT 0 34.350 0.800 46.050 ;
    RECT 0 46.350 0.800 46.650 ;
    RECT 0 46.950 0.800 47.250 ;
    RECT 0 47.550 0.800 47.850 ;
    RECT 0 48.150 0.800 48.450 ;
    RECT 0 48.750 0.800 49.050 ;
    RECT 0 49.350 0.800 49.650 ;
    RECT 0 49.950 0.800 50.250 ;
    RECT 0 50.550 0.800 50.850 ;
    RECT 0 51.150 0.800 51.450 ;
    RECT 0 51.750 0.800 52.050 ;
    RECT 0 52.350 0.800 52.650 ;
    RECT 0 52.950 0.800 53.250 ;
    RECT 0 53.550 0.800 53.850 ;
    RECT 0 54.150 0.800 54.450 ;
    RECT 0 54.750 0.800 55.050 ;
    RECT 0 55.350 0.800 55.650 ;
    RECT 0 55.950 0.800 56.250 ;
    RECT 0 56.550 0.800 56.850 ;
    RECT 0 57.150 0.800 57.450 ;
    RECT 0 57.750 0.800 58.050 ;
    RECT 0 58.350 0.800 58.650 ;
    RECT 0 58.950 0.800 59.250 ;
    RECT 0 59.550 0.800 59.850 ;
    RECT 0 60.150 0.800 60.450 ;
    RECT 0 60.750 0.800 61.050 ;
    RECT 0 61.350 0.800 61.650 ;
    RECT 0 61.950 0.800 62.250 ;
    RECT 0 62.550 0.800 62.850 ;
    RECT 0 63.150 0.800 63.450 ;
    RECT 0 63.750 0.800 64.050 ;
    RECT 0 64.350 0.800 64.650 ;
    RECT 0 64.950 0.800 65.250 ;
    RECT 0 65.550 0.800 65.850 ;
    RECT 0 66.150 0.800 66.450 ;
    RECT 0 66.750 0.800 67.050 ;
    RECT 0 67.350 0.800 67.650 ;
    RECT 0 67.950 0.800 68.250 ;
    RECT 0 68.550 0.800 68.850 ;
    RECT 0 69.150 0.800 69.450 ;
    RECT 0 69.750 0.800 70.050 ;
    RECT 0 70.350 0.800 70.650 ;
    RECT 0 70.950 0.800 71.250 ;
    RECT 0 71.550 0.800 71.850 ;
    RECT 0 72.150 0.800 72.450 ;
    RECT 0 72.750 0.800 73.050 ;
    RECT 0 73.350 0.800 73.650 ;
    RECT 0 73.950 0.800 74.250 ;
    RECT 0 74.550 0.800 86.250 ;
    RECT 0 86.550 0.800 86.850 ;
    RECT 0 87.150 0.800 87.450 ;
    RECT 0 87.750 0.800 88.050 ;
    RECT 0 88.350 0.800 88.650 ;
    RECT 0 88.950 0.800 89.250 ;
    RECT 0 89.550 0.800 89.850 ;
    RECT 0 90.150 0.800 90.450 ;
    RECT 0 90.750 0.800 91.050 ;
    RECT 0 91.350 0.800 91.650 ;
    RECT 0 91.950 0.800 92.250 ;
    RECT 0 92.550 0.800 92.850 ;
    RECT 0 93.150 0.800 93.450 ;
    RECT 0 93.750 0.800 94.050 ;
    RECT 0 94.350 0.800 94.650 ;
    RECT 0 94.950 0.800 95.250 ;
    RECT 0 95.550 0.800 95.850 ;
    RECT 0 96.150 0.800 96.450 ;
    RECT 0 96.750 0.800 97.050 ;
    RECT 0 97.350 0.800 97.650 ;
    RECT 0 97.950 0.800 98.250 ;
    RECT 0 98.550 0.800 98.850 ;
    RECT 0 99.150 0.800 99.450 ;
    RECT 0 99.750 0.800 100.050 ;
    RECT 0 100.350 0.800 100.650 ;
    RECT 0 100.950 0.800 101.250 ;
    RECT 0 101.550 0.800 101.850 ;
    RECT 0 102.150 0.800 102.450 ;
    RECT 0 102.750 0.800 103.050 ;
    RECT 0 103.350 0.800 103.650 ;
    RECT 0 103.950 0.800 104.250 ;
    RECT 0 104.550 0.800 104.850 ;
    RECT 0 105.150 0.800 105.450 ;
    RECT 0 105.750 0.800 106.050 ;
    RECT 0 106.350 0.800 106.650 ;
    RECT 0 106.950 0.800 107.250 ;
    RECT 0 107.550 0.800 107.850 ;
    RECT 0 108.150 0.800 108.450 ;
    RECT 0 108.750 0.800 109.050 ;
    RECT 0 109.350 0.800 109.650 ;
    RECT 0 109.950 0.800 110.250 ;
    RECT 0 110.550 0.800 110.850 ;
    RECT 0 111.150 0.800 111.450 ;
    RECT 0 111.750 0.800 112.050 ;
    RECT 0 112.350 0.800 112.650 ;
    RECT 0 112.950 0.800 113.250 ;
    RECT 0 113.550 0.800 113.850 ;
    RECT 0 114.150 0.800 114.450 ;
    RECT 0 114.750 0.800 126.450 ;
    RECT 0 126.750 0.800 127.050 ;
    RECT 0 127.350 0.800 127.650 ;
    RECT 0 127.950 0.800 128.250 ;
    RECT 0 128.550 0.800 128.850 ;
    RECT 0 129.150 0.800 140.850 ;
    RECT 0 141.150 0.800 141.450 ;
    RECT 0 141.750 0.800 142.050 ;
    RECT 0 142.350 0.800 182.240 ;
    LAYER met4 ;
    RECT 0 0 216.660 6.000 ;
    RECT 0 176.240 216.660 182.240 ;
    RECT 0.000 6.000 5.400 176.240 ;
    RECT 6.600 6.000 10.200 176.240 ;
    RECT 11.400 6.000 15.000 176.240 ;
    RECT 16.200 6.000 19.800 176.240 ;
    RECT 21.000 6.000 24.600 176.240 ;
    RECT 25.800 6.000 29.400 176.240 ;
    RECT 30.600 6.000 34.200 176.240 ;
    RECT 35.400 6.000 39.000 176.240 ;
    RECT 40.200 6.000 43.800 176.240 ;
    RECT 45.000 6.000 48.600 176.240 ;
    RECT 49.800 6.000 53.400 176.240 ;
    RECT 54.600 6.000 58.200 176.240 ;
    RECT 59.400 6.000 63.000 176.240 ;
    RECT 64.200 6.000 67.800 176.240 ;
    RECT 69.000 6.000 72.600 176.240 ;
    RECT 73.800 6.000 77.400 176.240 ;
    RECT 78.600 6.000 82.200 176.240 ;
    RECT 83.400 6.000 87.000 176.240 ;
    RECT 88.200 6.000 91.800 176.240 ;
    RECT 93.000 6.000 96.600 176.240 ;
    RECT 97.800 6.000 101.400 176.240 ;
    RECT 102.600 6.000 106.200 176.240 ;
    RECT 107.400 6.000 111.000 176.240 ;
    RECT 112.200 6.000 115.800 176.240 ;
    RECT 117.000 6.000 120.600 176.240 ;
    RECT 121.800 6.000 125.400 176.240 ;
    RECT 126.600 6.000 130.200 176.240 ;
    RECT 131.400 6.000 135.000 176.240 ;
    RECT 136.200 6.000 139.800 176.240 ;
    RECT 141.000 6.000 144.600 176.240 ;
    RECT 145.800 6.000 149.400 176.240 ;
    RECT 150.600 6.000 154.200 176.240 ;
    RECT 155.400 6.000 159.000 176.240 ;
    RECT 160.200 6.000 163.800 176.240 ;
    RECT 165.000 6.000 168.600 176.240 ;
    RECT 169.800 6.000 173.400 176.240 ;
    RECT 174.600 6.000 178.200 176.240 ;
    RECT 179.400 6.000 183.000 176.240 ;
    RECT 184.200 6.000 187.800 176.240 ;
    RECT 189.000 6.000 192.600 176.240 ;
    RECT 193.800 6.000 197.400 176.240 ;
    RECT 198.600 6.000 202.200 176.240 ;
    RECT 203.400 6.000 207.000 176.240 ;
    RECT 208.200 6.000 216.660 176.240 ;
    LAYER OVERLAP ;
    RECT 0 0 216.660 182.240 ;
  END
END liteeth_1rw1r_48w32d_sram

END LIBRARY
